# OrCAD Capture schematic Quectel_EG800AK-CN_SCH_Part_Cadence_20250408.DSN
size A2

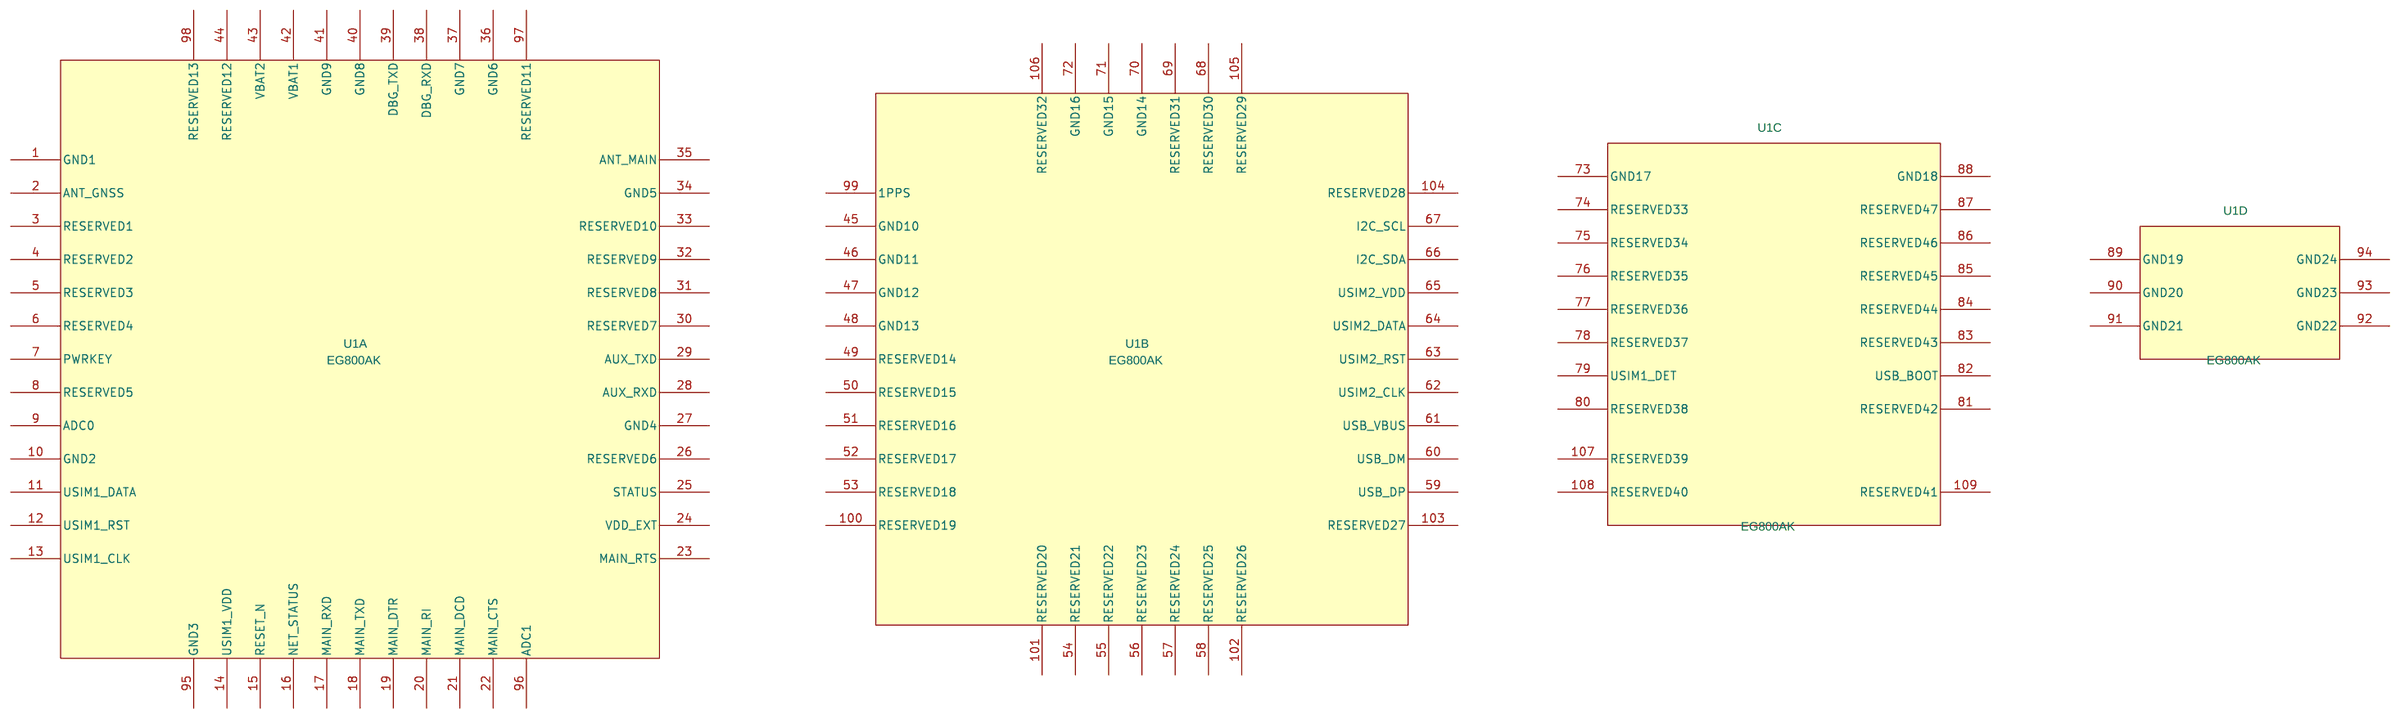
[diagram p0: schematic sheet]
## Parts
U1  EG800AK  [EG800AK]  (sections A,B,C,D)

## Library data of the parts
U1 = EG800AK

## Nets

Not connected (* = marked no-connect by the designer): U1 1(GND1) 2(ANT_GNSS) 3(RESERVED1) 4(RESERVED2) 5(RESERVED3) 6(RESERVED4) 7(PWRKEY) 8(RESERVED5) 9(ADC0) 10(GND2) 11(USIM1_DATA) 12(USIM1_RST) 13(USIM1_CLK) 14(USIM1_VDD) 15(RESET_N) 16(NET_STATUS) 17(MAIN_RXD) 18(MAIN_TXD) 19(MAIN_DTR) 20(MAIN_RI) 21(MAIN_DCD) 22(MAIN_CTS) 23(MAIN_RTS) 24(VDD_EXT) 25(STATUS) 26(RESERVED6) 27(GND4) 28(AUX_RXD) 29(AUX_TXD) 30(RESERVED7) 31(RESERVED8) 32(RESERVED9) 33(RESERVED10) 34(GND5) 35(ANT_MAIN) 36(GND6) 37(GND7) 38(DBG_RXD) 39(DBG_TXD) 40(GND8) 41(GND9) 42(VBAT1) 43(VBAT2) 44(RESERVED12) 45(GND10) 46(GND11) 47(GND12) 48(GND13) 49(RESERVED14) 50(RESERVED15) 51(RESERVED16) 52(RESERVED17) 53(RESERVED18) 54(RESERVED21) 55(RESERVED22) 56(RESERVED23) 57(RESERVED24) 58(RESERVED25) 59(USB_DP) 60(USB_DM) 61(USB_VBUS) 62(USIM2_CLK) 63(USIM2_RST) 64(USIM2_DATA) 65(USIM2_VDD) 66(I2C_SDA) 67(I2C_SCL) 68(RESERVED30) 69(RESERVED31) 70(GND14) 71(GND15) 72(GND16) 73(GND17) 74(RESERVED33) 75(RESERVED34) 76(RESERVED35) 77(RESERVED36) 78(RESERVED37) 79(USIM1_DET) 80(RESERVED38) 81(RESERVED42) 82(USB_BOOT) 83(RESERVED43) 84(RESERVED44) 85(RESERVED45) 86(RESERVED46) 87(RESERVED47) 88(GND18) 89(GND19) 90(GND20) 91(GND21) 92(GND22) 93(GND23) 94(GND24) 95(GND3) 96(ADC1) 97(RESERVED11) 98(RESERVED13) 99(1PPS) 100(RESERVED19) 101(RESERVED20) 102(RESERVED26) 103(RESERVED27) 104(RESERVED28) 105(RESERVED29) 106(RESERVED32) 107(RESERVED39) 108(RESERVED40) 109(RESERVED41)
